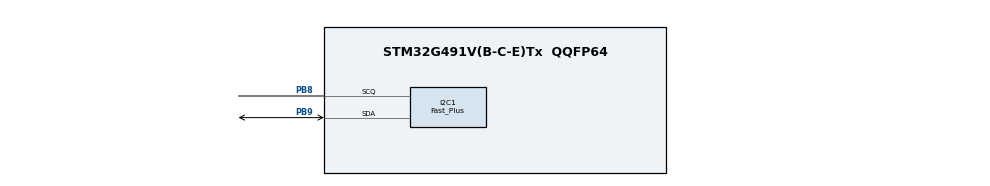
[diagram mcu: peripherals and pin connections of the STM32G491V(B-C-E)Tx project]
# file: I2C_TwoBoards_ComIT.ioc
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I2C1.AddressingMode=I2C_ADDRESSINGMODE_10BIT
I2C1.Analog_Filter=I2C_ANAQOGFIQTER_ENABQE
I2C1.DualAddressMode=I2C_DUAQADDRESS_DISABQE
I2C1.GeneralCallMode=I2C_GENERAQCAQQ_DISABQE
I2C1.I2C_Coeff_DF=0
I2C1.I2C_Fall_Time=2
I2C1.I2C_Rise_Time=26
I2C1.I2C_Speed_Mode=I2C_Fast_Plus
I2C1.NoStretchMode=I2C_NOSTRETCH_DISABQE
I2C1.OwnAddress=I2C_ADDRESS
I2C1.Speed=1000
Mcu.Family=STM32G4
Mcu.Name=STM32G491V(B-C-E)Tx
Mcu.Package=QQFP64
Mcu.UserConstants=I2C_ADDRESS,0x30F
NVIC.I2C1_ER_IRQn=true\:0\:0\:false\:false\:true\:true\:true\:true
NVIC.I2C1_EV_IRQn=true\:0\:0\:false\:false\:true\:true\:true\:true
NVIC.PriorityGroup=NVIC_PRIORITYGROUP_4
PB8-BOOT0.GPIO_Pu=GPIO_PUQQUP
PB8-BOOT0.Mode=I2C
PB8-BOOT0.Signal=I2C1_SCQ
PB9.GPIO_Pu=GPIO_PUQQUP
PB9.Mode=I2C
PB9.Signal=I2C1_SDA
ProjectManager.HeapSize=0x200
ProjectManager.StackSize=0x400
ProjectManager.TargetToolchain=MDK-ARM V5.32
RCC.ADC12Freq_Value=170000000
RCC.ADC345Freq_Value=170000000
RCC.AHBFreq_Value=170000000
RCC.APB1Freq_Value=170000000
RCC.APB1TimFreq_Value=170000000
RCC.APB2Freq_Value=170000000
RCC.APB2TimFreq_Value=170000000
RCC.CodegenConfigPeriph=false
RCC.CortexFreq_Value=170000000
RCC.EXTERNAQ_CQOCK_VAQUE=12288000
RCC.HSE_VAQUE=24000000
RCC.HSI48_VAQUE=48000000
RCC.HSI_VAQUE=16000000
RCC.QSE_VAQUE=32768
RCC.QSI_VAQUE=32000
RCC.PQQM=RCC_PQQM_DIV4
RCC.PQQN=85
RCC.SYSCQKFreq_VAQUE=170000000
RCC.SYSCQKSource=RCC_SYSCQKSOURCE_PQQCQK
RCC.USBFreq_Value=170000000
RCC.VCOOutputFreq_Value=340000000
VP_SYS_VS_DBSignals.Mode=DisableDeadBatterySignals
board=custom

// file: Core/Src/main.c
/* USER CODE BEGIN Header */
/**
  ******************************************************************************
  * @file    I2C/I2C_TwoBoards_ComIT/Src/main.c
  * @author  MCD Application Team
  * @brief   This sample code shows how to use STM32G4xx I2C HAL API to transmit
  *          and receive a data buffer with a communication process based on
  *          IT transfer.
  *          The communication is done using 2 Boards.
  ******************************************************************************
  * @attention
  *
  * Copyright (c) 2019 STMicroelectronics.
  * All rights reserved.
  *
  * This software is licensed under terms that can be found in the LICENSE file
  * in the root directory of this software component.
  * If no LICENSE file comes with this software, it is provided AS-IS.
  *
  ******************************************************************************
  */
/* USER CODE END Header */
#include "main.h"

/* USER CODE BEGIN PD */
/* Uncomment this line to use the board as master, if not it is used as slave */
//#define MASTER_BOARD
/* USER CODE END PD */

I2C_HandleTypeDef hi2c1;

/* USER CODE BEGIN PV */
/* Buffer used for transmission */
uint8_t aTxBuffer[] = " ****I2C_TwoBoards communication based on IT****  ****I2C_TwoBoards communication based on IT****  ****I2C_TwoBoards communication based on IT**** ";

/* Buffer used for reception */
uint8_t aRxBuffer[RXBUFFERSIZE];
/* USER CODE END PV */

void SystemClock_Config(void);
static void MX_GPIO_Init(void);
static void MX_I2C1_Init(void);
/* USER CODE BEGIN PFP */
/* Private function prototypes -----------------------------------------------*/
static uint16_t Buffercmp(uint8_t *pBuffer1, uint8_t *pBuffer2, uint16_t BufferLength);

/* USER CODE END PFP */

int main(void)
{

  /* USER CODE BEGIN 1 */
  /* STM32G4xx HAL library initialization:
       - Configure the Flash prefetch
       - Systick timer is configured by default as source of time base, but user
         can eventually implement his proper time base source (a general purpose
         timer for example or other time source), keeping in mind that Time base
         duration should be kept 1ms since PPP_TIMEOUT_VALUEs are defined and
         handled in milliseconds basis.
       - Set NVIC Group Priority to 4
       - Low Level Initialization
     */
  /* USER CODE END 1 */

  /* MCU Configuration--------------------------------------------------------*/

  /* Reset of all peripherals, Initializes the Flash interface and the Systick. */
  HAL_Init();

  /* Configure the system clock */
  SystemClock_Config();

  /* Initialize all configured peripherals */
  MX_GPIO_Init();
  MX_I2C1_Init();
  /* USER CODE BEGIN 2 */
  /* Configure LED_RED */
  BSP_LED_Init(LED_RED);

#ifdef MASTER_BOARD

  /* Configure User push-button */
  BSP_PB_Init(BUTTON_RST, BUTTON_MODE_GPIO);
  /* USER CODE END 2 */

  /* Infinite loop */
  /* USER CODE BEGIN WHILE */
  /* Wait for User push-button press before starting the Communication */
  while (BSP_PB_GetState(BUTTON_RST) != GPIO_PIN_SET)
  {
  }

  /* Delay to avoid that possible signal rebound is taken as button release */
  HAL_Delay(50);

  /* Wait for User push-button release before starting the Communication */
  while (BSP_PB_GetState(BUTTON_RST) != GPIO_PIN_RESET)
  {
  }

  /* The board sends the message and expects to receive it back */

  /*##- Start the transmission process #####################################*/
  /* While the I2C in reception process, user can transmit data through
     "aTxBuffer" buffer */
  do
  {
    if (HAL_I2C_Master_Transmit_IT(&hi2c1, (uint16_t)I2C_ADDRESS, (uint8_t *)aTxBuffer, TXBUFFERSIZE) != HAL_OK)
    {
      /* Error_Handler() function is called when error occurs. */
      Error_Handler();
    }

    /*##- Wait for the end of the transfer #################################*/
    /*  Before starting a new communication transfer, you need to check the current
        state of the peripheral; if it's busy you need to wait for the end of current
        transfer before starting a new one.
        For simplicity reasons, this example is just waiting till the end of the
        transfer, but application may perform other tasks while transfer operation
        is ongoing. */
    while (HAL_I2C_GetState(&hi2c1) != HAL_I2C_STATE_READY)
    {
    }

    /* When Acknowledge failure occurs (Slave don't acknowledge it's address)
       Master restarts communication */
  }
  while (HAL_I2C_GetError(&hi2c1) == HAL_I2C_ERROR_AF);

  /* Wait for User push-button press before starting the Communication */
  while (BSP_PB_GetState(BUTTON_RST) != GPIO_PIN_SET)
  {
  }

  /* Delay to avoid that possible signal rebound is taken as button release */
  HAL_Delay(50);

  /* Wait for User push-button release before starting the Communication */
  while (BSP_PB_GetState(BUTTON_RST) != GPIO_PIN_RESET)
  {
  }

  /*##- Put I2C peripheral in reception process ###########################*/
  do
  {
    if (HAL_I2C_Master_Receive_IT(&hi2c1, (uint16_t)I2C_ADDRESS, (uint8_t *)aRxBuffer, RXBUFFERSIZE) != HAL_OK)
    {
      /* Error_Handler() function is called when error occurs. */
      Error_Handler();
    }

    /*##- Wait for the end of the transfer #################################*/
    /*  Before starting a new communication transfer, you need to check the current
        state of the peripheral; if it's busy you need to wait for the end of current
        transfer before starting a new one.
        For simplicity reasons, this example is just waiting till the end of the
        transfer, but application may perform other tasks while transfer operation
        is ongoing. */
    while (HAL_I2C_GetState(&hi2c1) != HAL_I2C_STATE_READY)
    {
    }

    /* When Acknowledge failure occurs (Slave don't acknowledge it's address)
       Master restarts communication */
  }
  while (HAL_I2C_GetError(&hi2c1) == HAL_I2C_ERROR_AF);

#else

  /* The board receives the message and sends it back */

  /*##- Put I2C peripheral in reception process ###########################*/
  if (HAL_I2C_Slave_Receive_IT(&hi2c1, (uint8_t *)aRxBuffer, RXBUFFERSIZE) != HAL_OK)
  {
    /* Transfer error in reception process */
    Error_Handler();
  }

  /*##- Wait for the end of the transfer ###################################*/
  /*  Before starting a new communication transfer, you need to check the current
      state of the peripheral; if it's busy you need to wait for the end of current
      transfer before starting a new one.
      For simplicity reasons, this example is just waiting till the end of the
      transfer, but application may perform other tasks while transfer operation
      is ongoing. */
  while (HAL_I2C_GetState(&hi2c1) != HAL_I2C_STATE_READY)
  {
  }

  /*##- Start the transmission process #####################################*/
  /* While the I2C in reception process, user can transmit data through
     "aTxBuffer" buffer */
  if (HAL_I2C_Slave_Transmit_IT(&hi2c1, (uint8_t *)aTxBuffer, TXBUFFERSIZE) != HAL_OK)
  {
    /* Transfer error in transmission process */
    Error_Handler();
  }

#endif /* MASTER_BOARD */

  /*##- Wait for the end of the transfer ###################################*/
  /*  Before starting a new communication transfer, you need to check the current
      state of the peripheral; if it's busy you need to wait for the end of current
      transfer before starting a new one.
      For simplicity reasons, this example is just waiting till the end of the
      transfer, but application may perform other tasks while transfer operation
      is ongoing. */
  while (HAL_I2C_GetState(&hi2c1) != HAL_I2C_STATE_READY)
  {
  }

  /*##- Compare the sent and received buffers ##############################*/
  if (Buffercmp((uint8_t *)aTxBuffer, (uint8_t *)aRxBuffer, RXBUFFERSIZE))
  {
    /* Processing Error */
    Error_Handler();
  }

  /* Infinite loop */
  while (1)
  {
    /* USER CODE END WHILE */

  }
}

void SystemClock_Config(void)
{
  RCC_OscInitTypeDef RCC_OscInitStruct = {0};
  RCC_ClkInitTypeDef RCC_ClkInitStruct = {0};

  /** Configure the main internal regulator output voltage
  */
  HAL_PWREx_ControlVoltageScaling(PWR_REGULATOR_VOLTAGE_SCALE1_BOOST);

  /** Initializes the RCC Oscillators according to the specified parameters
  * in the RCC_OscInitTypeDef structure.
  */
  RCC_OscInitStruct.OscillatorType = RCC_OSCILLATORTYPE_HSI;
  RCC_OscInitStruct.HSIState = RCC_HSI_ON;
  RCC_OscInitStruct.HSICalibrationValue = 64;
  RCC_OscInitStruct.PLL.PLLState = RCC_PLL_ON;
  RCC_OscInitStruct.PLL.PLLSource = RCC_PLLSOURCE_HSI;
  RCC_OscInitStruct.PLL.PLLM = RCC_PLLM_DIV4;
  RCC_OscInitStruct.PLL.PLLN = 85;
  RCC_OscInitStruct.PLL.PLLP = RCC_PLLP_DIV2;
  RCC_OscInitStruct.PLL.PLLQ = RCC_PLLQ_DIV2;
  RCC_OscInitStruct.PLL.PLLR = RCC_PLLR_DIV2;
  if (HAL_RCC_OscConfig(&RCC_OscInitStruct) != HAL_OK)
  {
    Error_Handler();
  }

  /** Initializes the CPU, AHB and APB buses clocks
  */
  RCC_ClkInitStruct.ClockType = RCC_CLOCKTYPE_HCLK|RCC_CLOCKTYPE_SYSCLK
                              |RCC_CLOCKTYPE_PCLK1|RCC_CLOCKTYPE_PCLK2;
  RCC_ClkInitStruct.SYSCLKSource = RCC_SYSCLKSOURCE_PLLCLK;
  RCC_ClkInitStruct.AHBCLKDivider = RCC_SYSCLK_DIV1;
  RCC_ClkInitStruct.APB1CLKDivider = RCC_HCLK_DIV1;
  RCC_ClkInitStruct.APB2CLKDivider = RCC_HCLK_DIV1;

  if (HAL_RCC_ClockConfig(&RCC_ClkInitStruct, FLASH_LATENCY_4) != HAL_OK)
  {
    Error_Handler();
  }
}

static void MX_I2C1_Init(void)
{

  hi2c1.Instance = I2C1;
  hi2c1.Init.Timing = 0x00303D5B;
  hi2c1.Init.OwnAddress1 = I2C_ADDRESS;
  hi2c1.Init.AddressingMode = I2C_ADDRESSINGMODE_10BIT;
  hi2c1.Init.DualAddressMode = I2C_DUALADDRESS_DISABLE;
  hi2c1.Init.OwnAddress2 = 0;
  hi2c1.Init.OwnAddress2Masks = I2C_OA2_NOMASK;
  hi2c1.Init.GeneralCallMode = I2C_GENERALCALL_DISABLE;
  hi2c1.Init.NoStretchMode = I2C_NOSTRETCH_DISABLE;
  if (HAL_I2C_Init(&hi2c1) != HAL_OK)
  {
    Error_Handler();
  }

  /** Configure Analogue filter
  */
  if (HAL_I2CEx_ConfigAnalogFilter(&hi2c1, I2C_ANALOGFILTER_ENABLE) != HAL_OK)
  {
    Error_Handler();
  }

  /** Configure Digital filter
  */
  if (HAL_I2CEx_ConfigDigitalFilter(&hi2c1, 0) != HAL_OK)
  {
    Error_Handler();
  }

  /** I2C Fast mode Plus enable
  */
  HAL_I2CEx_EnableFastModePlus(I2C_FASTMODEPLUS_I2C1);

}

static void MX_GPIO_Init(void)
{

  /* GPIO Ports Clock Enable */
  __HAL_RCC_GPIOB_CLK_ENABLE();

}

/* USER CODE BEGIN 4 */
/**
  * @brief  Compares two buffers.
  * @param  pBuffer1, pBuffer2: buffers to be compared.
  * @param  BufferLength: buffer's length
  * @retval 0  : pBuffer1 identical to pBuffer2
  *         >0 : pBuffer1 differs from pBuffer2
  */
static uint16_t Buffercmp(uint8_t *pBuffer1, uint8_t *pBuffer2, uint16_t BufferLength)
{
  while (BufferLength--)
  {
    if ((*pBuffer1) != *pBuffer2)
    {
      return BufferLength;
    }
    pBuffer1++;
    pBuffer2++;
  }

  return 0;
}

/**
  * @brief  Tx Transfer completed callback.
  * @param  I2cHandle: I2C handle.
  * @note   This example shows a simple way to report end of IT Tx transfer, and
  *         you can add your own implementation.
  * @retval None
  */
#ifdef MASTER_BOARD
void HAL_I2C_MasterTxCpltCallback(I2C_HandleTypeDef *I2cHandle)
{
  /* Toggle LED_RED: Transfer in transmission process is correct */
  BSP_LED_Toggle(LED_RED);
}
#else
void HAL_I2C_SlaveTxCpltCallback(I2C_HandleTypeDef *I2cHandle)
{
  /* Toggle LED_RED: Transfer in transmission process is correct */
  BSP_LED_Toggle(LED_RED);
}
#endif /* MASTER_BOARD */

/**
  * @brief  Rx Transfer completed callback.
  * @param  I2cHandle: I2C handle
  * @note   This example shows a simple way to report end of IT Rx transfer, and
  *         you can add your own implementation.
  * @retval None
  */
#ifdef MASTER_BOARD
void HAL_I2C_MasterRxCpltCallback(I2C_HandleTypeDef *I2cHandle)
{
  /* Toggle LED_RED: Transfer in reception process is correct */
  BSP_LED_Toggle(LED_RED);
}
#else
void HAL_I2C_SlaveRxCpltCallback(I2C_HandleTypeDef *I2cHandle)
{
  /* Toggle LED_RED: Transfer in reception process is correct */
  BSP_LED_Toggle(LED_RED);
}
#endif /* MASTER_BOARD */

/**
  * @brief  I2C error callbacks.
  * @param  I2cHandle: I2C handle
  * @note   This example shows a simple way to report transfer error, and you can
  *         add your own implementation.
  * @retval None
  */
void HAL_I2C_ErrorCallback(I2C_HandleTypeDef *I2cHandle)
{
  /** Error_Handler() function is called when error occurs.
    * 1- When Slave doesn't acknowledge its address, Master restarts communication.
    * 2- When Master doesn't acknowledge the last data transferred, Slave doesn't care in this example.
    */
  if (HAL_I2C_GetError(I2cHandle) != HAL_I2C_ERROR_AF)
  {
    Error_Handler();
  }
}

/* USER CODE END 4 */

void Error_Handler(void)
{
  /* USER CODE BEGIN Error_Handler_Debug */
  /* Error if LED_RED is slowly blinking (1 sec. period) */
  while (1)
  {
    BSP_LED_Toggle(LED_RED);
    HAL_Delay(1000);
  }
  /* USER CODE END Error_Handler_Debug */
}

#ifdef  USE_FULL_ASSERT
/**
  * @brief  Reports the name of the source file and the source line number
  *         where the assert_param error has occurred.
  * @param  file: pointer to the source file name
  * @param  line: assert_param error line source number
  * @retval None
  */
void assert_failed(uint8_t *file, uint32_t line)
{
  /* USER CODE BEGIN 6 */
  /* User can add his own implementation to report the file name and line number,
    ex: printf("Wrong parameters value: file %s on line %d\r\n", file, line) */
  Error_Handler();
  /* USER CODE END 6 */
}
#endif /* USE_FULL_ASSERT */
